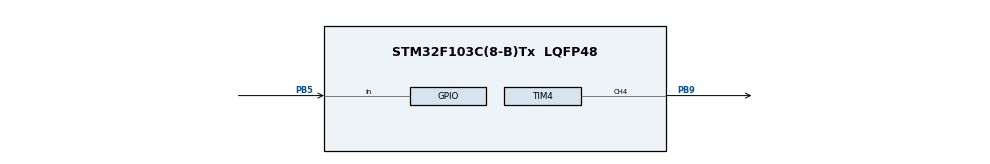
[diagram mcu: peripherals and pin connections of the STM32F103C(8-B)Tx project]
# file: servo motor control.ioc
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Mcu.Family=STM32F1
Mcu.Name=STM32F103C(8-B)Tx
Mcu.Package=LQFP48
NVIC.PriorityGroup=NVIC_PRIORITYGROUP_4
PB5.Signal=GPIO_Input
PB9.Signal=S_TIM4_CH4
PD0-OSC_IN.Mode=HSE-External-Oscillator
PD0-OSC_IN.Signal=RCC_OSC_IN
PD1-OSC_OUT.Mode=HSE-External-Oscillator
PD1-OSC_OUT.Signal=RCC_OSC_OUT
ProjectManager.HeapSize=0x200
ProjectManager.StackSize=0x400
ProjectManager.TargetToolchain=STM32CubeIDE
RCC.APB1Freq_Value=8000000
RCC.APB2Freq_Value=8000000
SH.S_TIM4_CH4.0=TIM4_CH4,PWM Generation4 CH4
TIM4.Channel-PWM\ Generation4\ CH4=TIM_CHANNEL_4
TIM4.Period=19999
TIM4.Prescaler=71
VP_SYS_VS_ND.Mode=No_Debug
VP_TIM4_VS_ClockSourceINT.Mode=Internal
board=custom

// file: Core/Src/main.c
/* USER CODE BEGIN Header */
/**
  ******************************************************************************
  * @file           : main.c
  * @brief          : Main program body
  ******************************************************************************
  * @attention
  *
  * Copyright (c) 2026 STMicroelectronics.
  * All rights reserved.
  *
  * This software is licensed under terms that can be found in the LICENSE file
  * in the root directory of this software component.
  * If no LICENSE file comes with this software, it is provided AS-IS.
  *
  ******************************************************************************
  */
/* USER CODE END Header */
#include "main.h"

TIM_HandleTypeDef htim4;

void SystemClock_Config(void);
static void MX_GPIO_Init(void);
static void MX_TIM4_Init(void);

int main(void)
{

  /* MCU Configuration--------------------------------------------------------*/

  /* Reset of all peripherals, Initializes the Flash interface and the Systick. */
  HAL_Init();

  /* Configure the system clock */
  SystemClock_Config();

  /* Initialize all configured peripherals */
  MX_GPIO_Init();
  MX_TIM4_Init();
  /* USER CODE BEGIN 2 */
  HAL_TIM_PWM_Start(&htim4 , TIM_CHANNEL_4);
  /* USER CODE END 2 */

  /* Infinite loop */
  /* USER CODE BEGIN WHILE */
  int hart_bit = 0 ;
  int last_press =1;
  int current_press =0;
  int state =0;
  int delay =0 ;
  while (1)
  {

    /* USER CODE END WHILE */

    /* USER CODE BEGIN 3 */
	  if(HAL_GetTick()-hart_bit >= 500){
		  hart_bit = HAL_GetTick();
	  	  HAL_GPIO_TogglePin(GPIOC , GPIO_PIN_13);

	  }
	  current_press = HAL_GPIO_ReadPin(GPIOB, GPIO_PIN_5);

	  if (last_press ==0 && current_press == 1){

		  if (HAL_GetTick()-delay >= 50){
			  delay = HAL_GetTick();

		  if (state ==0)
		  {

		__HAL_TIM_SET_COMPARE(&htim4, TIM_CHANNEL_4, 500);
		state++;
		  }
		  else if (state ==1)
		 		  {

		 		__HAL_TIM_SET_COMPARE(&htim4, TIM_CHANNEL_4, 1500);
				state++;

		 		  }
		  else if (state ==2)
		 		  {

		 		__HAL_TIM_SET_COMPARE(&htim4, TIM_CHANNEL_4, 2500);
		 		state = 0 ;

		 		  }

		  }

	  }
	  last_press = current_press ;

  }
  /* USER CODE END 3 */
}

void SystemClock_Config(void)
{
  RCC_OscInitTypeDef RCC_OscInitStruct = {0};
  RCC_ClkInitTypeDef RCC_ClkInitStruct = {0};

  /** Initializes the RCC Oscillators according to the specified parameters
  * in the RCC_OscInitTypeDef structure.
  */
  RCC_OscInitStruct.OscillatorType = RCC_OSCILLATORTYPE_HSE;
  RCC_OscInitStruct.HSEState = RCC_HSE_ON;
  RCC_OscInitStruct.HSEPredivValue = RCC_HSE_PREDIV_DIV1;
  RCC_OscInitStruct.HSIState = RCC_HSI_ON;
  RCC_OscInitStruct.PLL.PLLState = RCC_PLL_ON;
  RCC_OscInitStruct.PLL.PLLSource = RCC_PLLSOURCE_HSE;
  RCC_OscInitStruct.PLL.PLLMUL = RCC_PLL_MUL9;
  if (HAL_RCC_OscConfig(&RCC_OscInitStruct) != HAL_OK)
  {
    Error_Handler();
  }

  /** Initializes the CPU, AHB and APB buses clocks
  */
  RCC_ClkInitStruct.ClockType = RCC_CLOCKTYPE_HCLK|RCC_CLOCKTYPE_SYSCLK
                              |RCC_CLOCKTYPE_PCLK1|RCC_CLOCKTYPE_PCLK2;
  RCC_ClkInitStruct.SYSCLKSource = RCC_SYSCLKSOURCE_PLLCLK;
  RCC_ClkInitStruct.AHBCLKDivider = RCC_SYSCLK_DIV1;
  RCC_ClkInitStruct.APB1CLKDivider = RCC_HCLK_DIV2;
  RCC_ClkInitStruct.APB2CLKDivider = RCC_HCLK_DIV1;

  if (HAL_RCC_ClockConfig(&RCC_ClkInitStruct, FLASH_LATENCY_2) != HAL_OK)
  {
    Error_Handler();
  }
}

static void MX_TIM4_Init(void)
{

  TIM_ClockConfigTypeDef sClockSourceConfig = {0};
  TIM_MasterConfigTypeDef sMasterConfig = {0};
  TIM_OC_InitTypeDef sConfigOC = {0};

  htim4.Instance = TIM4;
  htim4.Init.Prescaler = 71;
  htim4.Init.CounterMode = TIM_COUNTERMODE_UP;
  htim4.Init.Period = 19999;
  htim4.Init.ClockDivision = TIM_CLOCKDIVISION_DIV1;
  htim4.Init.AutoReloadPreload = TIM_AUTORELOAD_PRELOAD_DISABLE;
  if (HAL_TIM_Base_Init(&htim4) != HAL_OK)
  {
    Error_Handler();
  }
  sClockSourceConfig.ClockSource = TIM_CLOCKSOURCE_INTERNAL;
  if (HAL_TIM_ConfigClockSource(&htim4, &sClockSourceConfig) != HAL_OK)
  {
    Error_Handler();
  }
  if (HAL_TIM_PWM_Init(&htim4) != HAL_OK)
  {
    Error_Handler();
  }
  sMasterConfig.MasterOutputTrigger = TIM_TRGO_RESET;
  sMasterConfig.MasterSlaveMode = TIM_MASTERSLAVEMODE_DISABLE;
  if (HAL_TIMEx_MasterConfigSynchronization(&htim4, &sMasterConfig) != HAL_OK)
  {
    Error_Handler();
  }
  sConfigOC.OCMode = TIM_OCMODE_PWM1;
  sConfigOC.Pulse = 0;
  sConfigOC.OCPolarity = TIM_OCPOLARITY_HIGH;
  sConfigOC.OCFastMode = TIM_OCFAST_DISABLE;
  if (HAL_TIM_PWM_ConfigChannel(&htim4, &sConfigOC, TIM_CHANNEL_4) != HAL_OK)
  {
    Error_Handler();
  }
  HAL_TIM_MspPostInit(&htim4);

}

static void MX_GPIO_Init(void)
{
  GPIO_InitTypeDef GPIO_InitStruct = {0};

  /* GPIO Ports Clock Enable */
  __HAL_RCC_GPIOC_CLK_ENABLE();
  __HAL_RCC_GPIOD_CLK_ENABLE();
  __HAL_RCC_GPIOA_CLK_ENABLE();
  __HAL_RCC_GPIOB_CLK_ENABLE();

  /*Configure GPIO pin Output Level */
  HAL_GPIO_WritePin(GPIOC, GPIO_PIN_13, GPIO_PIN_RESET);

  /*Configure GPIO pin Output Level */
  HAL_GPIO_WritePin(GPIOA, GPIO_PIN_7, GPIO_PIN_RESET);

  /*Configure GPIO pin : PC13 */
  GPIO_InitStruct.Pin = GPIO_PIN_13;
  GPIO_InitStruct.Mode = GPIO_MODE_OUTPUT_PP;
  GPIO_InitStruct.Pull = GPIO_NOPULL;
  GPIO_InitStruct.Speed = GPIO_SPEED_FREQ_LOW;
  HAL_GPIO_Init(GPIOC, &GPIO_InitStruct);

  /*Configure GPIO pin : PA7 */
  GPIO_InitStruct.Pin = GPIO_PIN_7;
  GPIO_InitStruct.Mode = GPIO_MODE_OUTPUT_PP;
  GPIO_InitStruct.Pull = GPIO_NOPULL;
  GPIO_InitStruct.Speed = GPIO_SPEED_FREQ_LOW;
  HAL_GPIO_Init(GPIOA, &GPIO_InitStruct);

  /*Configure GPIO pin : PB5 */
  GPIO_InitStruct.Pin = GPIO_PIN_5;
  GPIO_InitStruct.Mode = GPIO_MODE_INPUT;
  GPIO_InitStruct.Pull = GPIO_NOPULL;
  HAL_GPIO_Init(GPIOB, &GPIO_InitStruct);

}

void Error_Handler(void)
{
  __disable_irq();
  while (1)
  {
  }
}
